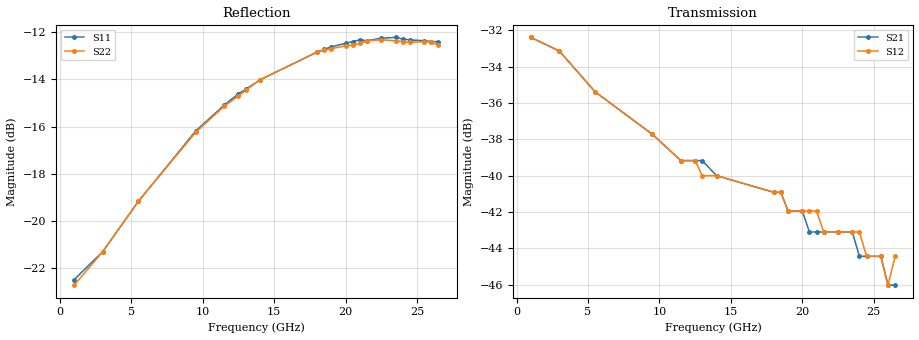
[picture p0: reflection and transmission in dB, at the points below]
! HMMC-1015
! S-PARAMETERS  at  Maximum Attenuation;  V1 = -4V;  V2 = 0V.  LAST UPDATED  02-25-97
#  GHZ  S  MA  R  50
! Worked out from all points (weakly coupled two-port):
!   52 points, 1 GHz to 26.5 GHz, reference 50 ohm
!   highest |S21| = -32.40 dB at 1 GHz (marker M1); lowest = -46.0 dB at 26 GHz (marker M2)
!   lowest |S11| = -22.5 dB at 1 GHz (marker M3), VSWR 1.16, Z = 57.8 - j2.26 ohm
!   |S11| at or under -10 dB: start of sweep to end of sweep
!   |S22| runs from -22.7 to -12.3 dB; largest |S21 - S12| = 0.0011
!   S11 on the Smith chart (normalised r, x): 1 GHz: 1.16, -0.05; 12.5 GHz: 0.81, -0.28; 26.5 GHz: 0.62, +0.09
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1  0.075 -15.0  0.024 -12.0  0.024 -12.0  0.073 -15.0
3  0.086 -39.0  0.022 -32.0  0.022 -32.0  0.086 -38.0
5.5  0.11 -66.0  0.017 -53.0  0.017 -53.0  0.11 -66.0
9.5  0.155 -96.0  0.013 -74.0  0.013 -74.0  0.154 -97.0
11.5  0.176 -110.0  0.011 -82.0  0.011 -82.0  0.175 -110.0
12.5  0.186 -115.0  0.011 -85.0  0.011 -84.0  0.184 -116.0
13  0.19 -118.0  0.011 -87.0  0.01 -86.0  0.189 -119.0
14  0.199 -124.0  0.01 -91.0  0.01 -92.0  0.199 -125.0
18  0.228 -147.0  0.009 -109.0  0.009 -109.0  0.228 -149.0
18.5  0.231 -149.0  0.009 -112.0  0.009 -112.0  0.23 -151.0
19  0.234 -152.0  0.008 -116.0  0.008 -116.0  0.232 -154.0
20  0.238 -158.0  0.008 -118.0  0.008 -117.0  0.235 -160.0
20.5  0.24 -160.0  0.007 -119.0  0.008 -120.0  0.236 -163.0
21  0.242 -163.0  0.007 -120.0  0.008 -123.0  0.238 -166.0
21.5  0.241 -166.0  0.007 -125.0  0.007 -125.0  0.241 -169.0
22.5  0.244 -172.0  0.007 -128.0  0.007 -131.0  0.242 -174.0
23.5  0.245 -177.0  0.007 -138.0  0.007 -138.0  0.241 180.0
24  0.243 180.0  0.006 -141.0  0.007 -143.0  0.24 177.0
24.5  0.242 176.0  0.006 -145.0  0.006 -141.0  0.239 174.0
25.5  0.241 171.0  0.006 -144.0  0.006 -144.0  0.24 167.0
26  0.24 167.0  0.005 -145.0  0.005 -140.0  0.239 164.0
26.5  0.24 164.0  0.005 -143.0  0.006 -140.0  0.236 161.0
